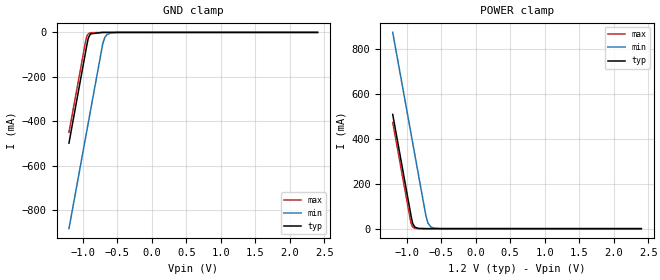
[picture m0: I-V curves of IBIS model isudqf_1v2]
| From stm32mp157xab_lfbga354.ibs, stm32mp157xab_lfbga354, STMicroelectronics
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[Model]   isudqf_1v2
Model_type Input
Polarity   Non-Inverting
Enable   Active-Low
| CAP_THRESHOLD on pad IOFT is "UDTCAPC" :
| Rising=20.00f vddiom   Falling=80.00f vddiom
| C_comp min and max val. don't necessarily correlate with the min and max pvt
| but are the smallest and greatest pad capacitance found.
| var   typ   min   max
C_comp   1.06084pF  1.04257pF  1.07176pF
|C_comp_pullup   463.02500fF  442.93500fF  461.80500fF
|C_comp_pulldown   597.81000fF  599.63000fF  609.95500fF
Vinl = 360.0mV
Vinh = 792.0mV
[Model Spec]
| TIME_THRESHOLD on pin ZIV11 is "CMOS" :
| Rising=40.00f vdd   Falling=60.00f vdd
Vinl 595.60000mV 448.60000mV 652.60000mV
Vinh 595.40000mV 448.40000mV 652.40000mV
| variable   typ   min   max
[Temperature Range] 25.0 140.0 -40.0
| variable   typ   min   max
[Voltage Range] 1.2V 900.0mV 1.32V
| variable   typ   min   max
[POWER Clamp Reference] 1.2V 900.0mV 1.32V
| variable   typ   min   max
[GND Clamp Reference] 0V 0V 0V
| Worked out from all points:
|   GND clamp passes 1 mA (typ) near -0.82 V on its own axis
|   POWER clamp passes 1 mA (typ) near -0.83 V on its own axis
[POWER Clamp]
-1.2V     508.8mA    874.1mA    473.5mA
-940mV    66.83mA    432.1mA    31.5mA
-930mV    49.83mA    415.1mA    19.15mA
-910mV    22.88mA    381.1mA    7.077mA
-880mV    7.117mA    330.1mA    1.59mA
-830mV    1.017mA    245.1mA    132uA
-720mV    14.05uA    58.12mA    553.9nA
-690mV    4.372uA    25.02mA    124.6nA
-650mV    921.8nA    8.137mA    17.13nA
-600mV    131.8nA    1.998mA    1.472nA
-490mV    1.914nA    90.93uA    27.04pA
2.4V      0A         0A         0A
[GND Clamp]
-1.2V     -497.4mA   -881.9mA   -449.4mA
-960mV    -89.41mA   -473.9mA   -41.39mA
-940mV    -55.41mA   -439.9mA   -16.04mA
-920mV    -26.33mA   -405.9mA   -6.567mA
-900mV    -12.55mA   -371.9mA   -2.962mA
-880mV    -6.152mA   -337.9mA   -1.53mA
-710mV    -61.3uA    -49.97mA   -15.96uA
-680mV    -25.68uA   -21.93mA   -9.154uA
-650mV    -12.16uA   -9.779mA   -6.928uA
-590mV    -5.24uA    -2.109mA   -4.904uA
-470mV    -2.231uA   -127.2uA   -1.904uA
2.4V      73.34pA    30.52nA    19.17pA
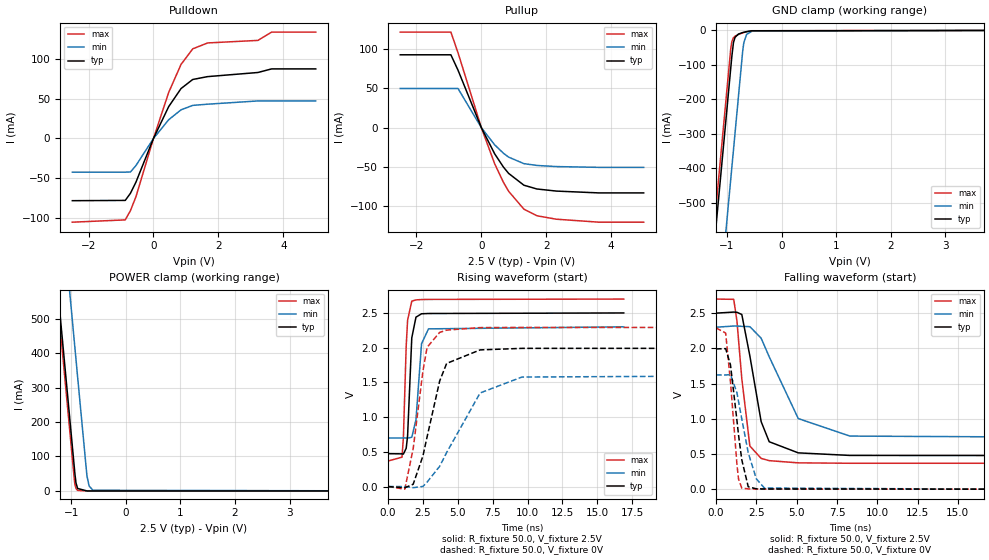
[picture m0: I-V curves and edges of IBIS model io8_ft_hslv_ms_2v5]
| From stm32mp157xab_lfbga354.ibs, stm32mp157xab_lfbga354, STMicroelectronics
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[Model]   io8_ft_hslv_ms_2v5
Model_type I/O
Polarity   Non-Inverting
Enable   Active-Low
| CAP_THRESHOLD on pad IOFT is "UDTCAPC" :
| Rising=20.00f vddiom   Falling=80.00f vddiom
| C_comp min and max val. don't necessarily correlate with the min and max pvt
| but are the smallest and greatest pad capacitance found.
| var   typ   min   max
C_comp   3.57714pF  3.54080pF  3.63508pF
|C_comp_pullup   2.11645pF  2.17895pF  2.03330pF
|C_comp_pulldown   1.46069pF  1.36185pF  1.60178pF
Vinl = 920.0mV
Vinh = 1.62V
Vmeas = 1.25V   | Reference voltage for timing measurements
Cref  = 50.0pF   | Timing specification test load capacitance value
Rref  = 100.0MOhm   | Timing specification test load resistance value
Vref  = 0V   | Timing specification test load voltage
[Model Spec]
| TIME_THRESHOLD on pin ZIV11 is "CMOS" :
| Rising=40.00f vdd   Falling=60.00f vdd
Vinl 1.03860V 964.60000mV 1.11860V
Vinh 1.36340V 1.26240V 1.44140V
| variable   typ   min   max
[Temperature Range] 25.0 140.0 -40.0
| variable   typ   min   max
[Voltage Range] 2.5V 2.3V 2.7V
| variable   typ   min   max
[POWER Clamp Reference] 2.5V 2.3V 2.7V
| variable   typ   min   max
[GND Clamp Reference] 0V 0V 0V
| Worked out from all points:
|   slope of the pulldown table from 0 to 0.375 V, typ, clamps not added: 11.3 ohm
|   slope of the pullup table from 0 to 0.375 V, typ, clamps not added: 12.3 ohm
|   GND clamp passes 1 mA (typ) near -0.52 V on its own axis
|   POWER clamp passes 1 mA (typ) near -0.83 V on its own axis
|   rising waveform, R_fixture 50.0, V_fixture 2.5V: 20-80 % time 255ps typ, 336ps min, 239ps max; typ from 0.473 V to 2.5 V
|   falling waveform, R_fixture 50.0, V_fixture 2.5V: 20-80 % time 928ps typ, 1.92ns min, 578ps max; typ from 2.5 V to 0.473 V
|   rising waveform, R_fixture 50.0, V_fixture 0V: 20-80 % time 1.36ns typ, 2.59ns min, 884ps max; typ from 0 V to 1.99 V
|   falling waveform, R_fixture 50.0, V_fixture 0V: 20-80 % time 629ps typ, 869ps min, 474ps max; typ from 1.99 V to 0 V
[POWER Clamp]
-2.5V     2.719A     3.084A     2.683A
-1.28V    644.8mA    1.01A      609.5mA
-1.26V    610.8mA    976.1mA    575.5mA
-1.04V    236.8mA    602.1mA    201.5mA
-940mV    66.83mA    432.1mA    31.5mA
-930mV    49.83mA    415.1mA    19.15mA
-910mV    22.88mA    381.1mA    7.077mA
-880mV    7.117mA    330.1mA    1.59mA
-710mV    9.523uA    43.89mA    337nA
-670mV    2.008uA    14.27mA    46.3nA
-600mV    132.9nA    1.998mA    1.599nA
5V        0A         0A         0A
[GND Clamp]
-2.5V     -2.779A    -3.101A    -2.723A
-1.26V    -670.8mA   -992.7mA   -614.5mA
-930mV    -109.8mA   -431.7mA   -53.54mA
-910mV    -75.83mA   -397.7mA   -32.67mA
-880mV    -35.28mA   -346.7mA   -21.39mA
-850mV    -20.07mA   -295.7mA   -16.99mA
-790mV    -10.9mA    -193.7mA   -12.02mA
-710mV    -6.374mA   -57.93mA   -7.219mA
-690mV    -5.545mA   -35.45mA   -6.225mA
-640mV    -3.775mA   -11.96mA   -4.068mA
-540mV    -1.354mA   -2.661mA   -1.223mA
5V        6.965nA    2.133uA    347.4pA
| variable   typ   min   max
[Pullup Reference] 2.5V 2.3V 2.7V
| variable   typ   min   max
[Pulldown Reference] 0V 0V 0V
[Pullup]
-2.5V     92.89mA    49.95mA    121.8mA
-940mV    92.89mA    49.95mA    121.8mA
-720mV    73.31mA    49.95mA    95.5mA
0V        9.19pA     1.4nA      5.79pA
410mV     -33.26mA   -21.8mA    -45.97mA
680mV     -50.15mA   -32.52mA   -69.57mA
840mV     -58.17mA   -37.44mA   -80.95mA
1.31V     -73.2mA    -45.74mA   -103.7mA
1.71V     -78mA      -48.02mA   -112.1mA
2.31V     -80.68mA   -49.47mA   -116.5mA
3.63V     -83.02mA   -50.48mA   -120.3mA
5V        -83.02mA   -50.48mA   -120.3mA
[Pulldown]
-2.5V     -78.63mA   -42.6mA    -105.8mA
-870mV    -78.28mA   -42.6mA    -102.9mA
-710mV    -69.32mA   -42.37mA   -91.24mA
-540mV    -55.23mA   -34.22mA   -73.64mA
0V        0A         -2pA       0A
470mV     40.29mA    23.69mA    58.27mA
850mV     63.07mA    36.18mA    93.59mA
1.21V     74.52mA    41.78mA    113.2mA
1.67V     78.14mA    43.3mA     120.7mA
3.22V     83.36mA    47.41mA    123.9mA
3.64V     87.89mA    47.41mA    134.4mA
5V        87.89mA    47.41mA    134.4mA
[Ramp]
dV/dt_r 1.19545V/1.35568ns 973.40258mV/2.59049ns 1.37489V/880.07309ps
dV/dt_f 1.21605V/925.50477ps 960.47155mV/1.91927ns 1.39953V/573.33804ps
R_load = 50.0
| Removed startup time: 0s 0s 0s  .
| Removed end time: 16.9ns.
[Rising Waveform]
R_fixture   = 50.0
V_fixture   = 2.5V
V_fixture_min = 2.3V
V_fixture_max = 2.7V
0s        473.2mV    699.2mV    367.5mV
1ns       470.7mV    699.4mV    423.3mV
1.1ns     467.8mV    699.3mV    711.2mV
1.3ns     551.2mV    699.1mV    2.024V
1.4ns     728.5mV    698.3mV    2.395V
1.7ns     2.141V     709.2mV    2.67V
2ns       2.439V     960.9mV    2.688V
2.4ns     2.488V     2.057V     2.693V
2.9ns     2.492V     2.271V     2.695V
16.9ns    2.5V       2.3V       2.7V
| Removed startup time: 0s 0s 0s  .
| Removed end time: 54.9ns.
[Falling Waveform]
R_fixture   = 50.0
V_fixture   = 2.5V
V_fixture_min = 2.3V
V_fixture_max = 2.7V
0s        2.5V       2.3V       2.7V
1.1ns     2.515V     2.317V     2.696V
1.3ns     2.512V     2.317V     2.388V
1.6ns     2.481V     2.312V     1.571V
2.1ns     1.893V     2.308V     612.5mV
2.8ns     959.1mV    2.144V     437mV
3.3ns     673.5mV    1.88V      405mV
5.1ns     515.7mV    1.003V     373.7mV
8.3ns     479.1mV    753.9mV    367.9mV
54.9ns    473.2mV    699.2mV    367.5mV
| Removed startup time: 0s 0s 0s  .
| Removed end time: 54.9ns.
[Rising Waveform]
R_fixture   = 50.0
V_fixture   = 0V
V_fixture_min = 0V
V_fixture_max = 0V
0s        55.42nV    78.87nV    -3.786uV
1.2ns     -17.78mV   49.94uV    -37.72mV
1.8ns     33.06mV    -16.52mV   544.3mV
2.5ns     440.9mV    1.382mV    1.664V
2.8ns     716.9mV    64.67mV    2.006V
3.7ns     1.52V      291.4mV    2.22V
4.2ns     1.773V     489.6mV    2.253V
6.6ns     1.968V     1.348V     2.289V
9.6ns     1.99V      1.577V     2.291V
54.9ns    1.992V     1.622V     2.291V
| Removed startup time: 0s 0s 0s  .
| Removed end time: 16.9ns.
[Falling Waveform]
R_fixture   = 50.0
V_fixture   = 0V
V_fixture_min = 0V
V_fixture_max = 0V
0s        1.992V     1.622V     2.291V
600ps     1.996V     1.622V     2.217V
900ps     1.764V     1.626V     1.52V
1.3ns     974.4mV    1.369V     348.3mV
1.4ns     765.3mV    1.241V     141.8mV
1.6ns     416.5mV    996.7mV    14.99mV
2ns       33.71mV    515.9mV    4.27mV
2.5ns     5.236mV    147.1mV    2.52mV
3ns       3.046mV    16.4mV     1.808mV
16.9ns    6.795uV    40.09uV    3.014uV
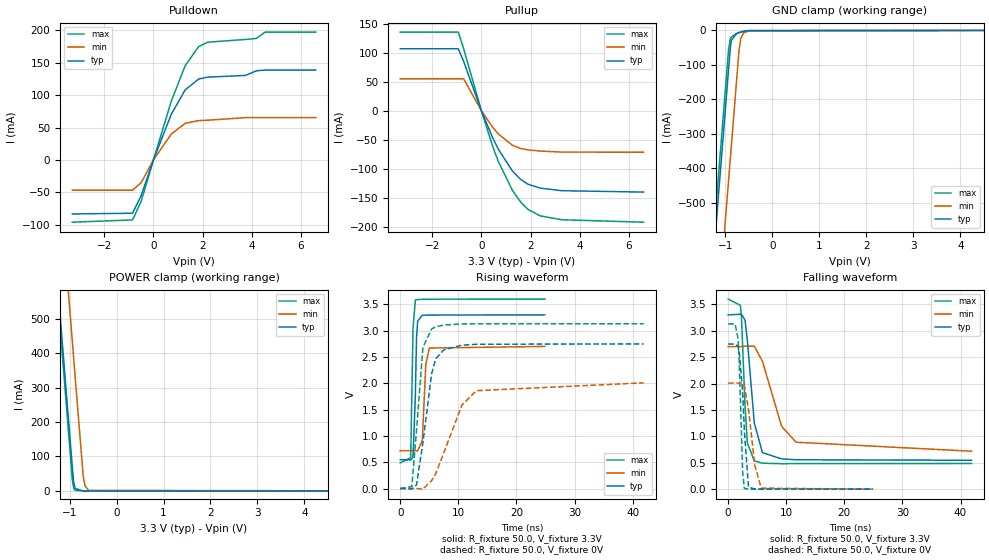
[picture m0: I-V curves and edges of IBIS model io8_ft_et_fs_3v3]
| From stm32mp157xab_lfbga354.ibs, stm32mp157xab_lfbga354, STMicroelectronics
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[Model]   io8_ft_et_fs_3v3
Model_type I/O
Polarity   Non-Inverting
Enable   Active-Low
| CAP_THRESHOLD on pad IOFT is "UDTCAPC" :
| Rising=20.00f vddiom   Falling=80.00f vddiom
| C_comp min and max val. don't necessarily correlate with the min and max pvt
| but are the smallest and greatest pad capacitance found.
| var   typ   min   max
C_comp   3.68632pF  3.64973pF  3.70805pF
|C_comp_pullup   2.21620pF  2.27950pF  2.11835pF
|C_comp_pulldown   1.47012pF  1.37023pF  1.58970pF
Vinl = 1.08V
Vinh = 2.16V
Vmeas = 1.65V   | Reference voltage for timing measurements
Cref  = 50.0pF   | Timing specification test load capacitance value
Rref  = 100.0MOhm   | Timing specification test load resistance value
Vref  = 0V   | Timing specification test load voltage
[Model Spec]
| TIME_THRESHOLD on pin ZIV11 is "CMOS" :
| Rising=40.00f vdd   Falling=60.00f vdd
Vinl 1.36060V 1.12960V 1.47360V
Vinh 1.71540V 1.45040V 1.82940V
| variable   typ   min   max
[Temperature Range] 25.0 140.0 -40.0
| variable   typ   min   max
[Voltage Range] 3.3V 2.7V 3.6V
| variable   typ   min   max
[POWER Clamp Reference] 3.3V 2.7V 3.6V
| variable   typ   min   max
[GND Clamp Reference] 0V 0V 0V
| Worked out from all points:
|   slope of the pulldown table from 0 to 0.495 V, typ, clamps not added: 9.86 ohm
|   slope of the pullup table from 0 to 0.495 V, typ, clamps not added: 9.93 ohm
|   GND clamp passes 1 mA (typ) near -0.52 V on its own axis
|   POWER clamp passes 1 mA (typ) near -0.83 V on its own axis
|   rising waveform, R_fixture 50.0, V_fixture 3.3V: 20-80 % time 297ps typ, 428ps min, 262ps max; typ from 0.547 V to 3.3 V
|   falling waveform, R_fixture 50.0, V_fixture 3.3V: 20-80 % time 1.31ns typ, 3.25ns min, 738ps max; typ from 3.3 V to 0.547 V
|   rising waveform, R_fixture 50.0, V_fixture 0V: 20-80 % time 1.9ns typ, 4.15ns min, 1.24ns max; typ from 0 V to 2.75 V
|   falling waveform, R_fixture 50.0, V_fixture 0V: 20-80 % time 775ps typ, 1.26ns min, 523ps max; typ from 2.75 V to 0 V
[POWER Clamp]
-3.3V     4.079A     4.444A     4.043A
-1.46V    950.8mA    1.316A     915.5mA
-1.28V    644.8mA    1.01A      609.5mA
-1.09V    321.8mA    687.1mA    286.5mA
-1.07V    287.8mA    653.1mA    252.5mA
-940mV    66.83mA    432.1mA    31.5mA
-910mV    22.88mA    381.1mA    7.077mA
-880mV    7.117mA    330.1mA    1.59mA
-710mV    9.525uA    43.89mA    337.5nA
-670mV    2.01uA     14.27mA    46.78nA
-590mV    92.5nA     1.508mA    1.51nA
6.6V      0A         0A         0A
[GND Clamp]
-3.3V     -4.139A    -4.461A    -4.081A
-1.26V    -670.8mA   -992.8mA   -613.3mA
-1.1V     -398.8mA   -720.8mA   -341.3mA
-930mV    -109.8mA   -431.8mA   -52.32mA
-890mV    -44.91mA   -363.8mA   -23.04mA
-870mV    -28.43mA   -329.8mA   -18.86mA
-760mV    -8.879mA   -142.8mA   -9.749mA
-710mV    -6.383mA   -58.04mA   -7.036mA
-670mV    -4.798mA   -22.41mA   -5.193mA
-610mV    -2.902mA   -7.057mA   -2.962mA
-500mV    -778.4uA   -1.643mA   -611.3uA
6.6V      9.268nA    3.087uA    468pA
| variable   typ   min   max
[Pullup Reference] 3.3V 2.7V 3.6V
| variable   typ   min   max
[Pulldown Reference] 0V 0V 0V
[Pullup]
-3.3V     106.6mA    54.84mA    135.3mA
-940mV    106.6mA    54.84mA    135.3mA
-720mV    84.69mA    54.84mA    106.6mA
0V        11.24pA    1.438nA    7.78pA
470mV     -47.64mA   -29.17mA   -62.71mA
690mV     -66.39mA   -40.06mA   -87.4mA
1.26V     -103.7mA   -59.49mA   -136.9mA
1.59V     -118mA     -65.02mA   -156.8mA
1.89V     -126.5mA   -67.46mA   -169.8mA
2.39V     -133.2mA   -69.44mA   -181mA
3.27V     -137.7mA   -71.26mA   -187.7mA
6.6V      -140.1mA   -71.49mA   -191.9mA
[Pulldown]
-3.3V     -83.56mA   -46.9mA    -96.31mA
-850mV    -82.46mA   -46.9mA    -92.78mA
-500mV    -55.19mA   -35.23mA   -63.97mA
0V        30fA       -2pA       200fA
720mV     70.07mA    39.69mA    90.11mA
1.29V     108.2mA    56.55mA    145.7mA
1.84V     125mA      60.7mA     175.1mA
2.21V     127.9mA    61.3mA     181.9mA
3.74V     130.5mA    65.29mA    186.1mA
4.18V     137.6mA    65.29mA    187.7mA
4.54V     138.8mA    65.29mA    197.5mA
6.6V      138.8mA    65.29mA    197.5mA
[Ramp]
dV/dt_r 1.64855V/1.89725ns 1.20468V/4.14499ns 1.87853V/1.24008ns
dV/dt_f 1.65162V/1.31006ns 1.18883V/3.24747ns 1.86819V/736.45008ps
R_load = 50.0
| Removed startup time: 0s 0s 0s  .
| Removed end time: 24.9ns.
[Rising Waveform]
R_fixture   = 50.0
V_fixture   = 3.3V
V_fixture_min = 2.7V
V_fixture_max = 3.6V
0s        547.3mV    718.4mV    486.3mV
1.8ns     543.9mV    718.4mV    585.2mV
2.2ns     590.8mV    718.4mV    3.037V
2.6ns     1.76V      718.5mV    3.581V
2.8ns     2.857V     717.9mV    3.59V
3ns       3.181V     716.3mV    3.591V
3.8ns     3.293V     910.7mV    3.595V
4.4ns     3.294V     2.355V     3.596V
5ns       3.296V     2.669V     3.597V
24.9ns    3.3V       2.7V       3.6V
| Removed startup time: 0s 0s 0s  .
| Removed end time: 41.9ns.
[Falling Waveform]
R_fixture   = 50.0
V_fixture   = 3.3V
V_fixture_min = 2.7V
V_fixture_max = 3.6V
0s        3.3V       2.7V       3.6V
2.1ns     3.313V     2.7V       3.481V
2.3ns     3.311V     2.699V     3.246V
2.9ns     3.203V     2.709V     1.588V
3.3ns     2.824V     2.709V     872.7mV
4.5ns     1.255V     2.706V     536.5mV
5.9ns     692mV      2.423V     491.8mV
9.2ns     574mV      1.188V     482.3mV
11.7ns    556.5mV    889.2mV    484.5mV
41.9ns    547.3mV    718.6mV    486.3mV
| Removed startup time: 0s 0s 0s  .
| Removed end time: 41.9ns.
[Rising Waveform]
R_fixture   = 50.0
V_fixture   = 0V
V_fixture_min = 0V
V_fixture_max = 0V
0s        605.8nV    443.2nV    -450.2nV
2ns       -10.22mV   1.521uV    37.31mV
2.8ns     69.22mV    237.4uV    1.1V
3.9ns     868.5mV    -12.54mV   2.682V
5.4ns     2.178V     149.9mV    3.032V
6.1ns     2.466V     279.3mV    3.072V
7.5ns     2.635V     680.1mV    3.107V
10.6ns    2.724V     1.582V     3.127V
13.1ns    2.741V     1.859V     3.13V
41.9ns    2.748V     2.008V     3.131V
| Removed startup time: 0s 0s 0s  .
| Removed end time: 24.9ns.
[Falling Waveform]
R_fixture   = 50.0
V_fixture   = 0V
V_fixture_min = 0V
V_fixture_max = 0V
0s        2.748V     2.008V     3.131V
1.2ns     2.747V     2.008V     3.127V
1.7ns     2.706V     2.008V     2.851V
1.9ns     2.615V     2.008V     2.43V
2.5ns     1.824V     2.012V     311.5mV
2.8ns     1.089V     1.951V     11.64mV
3.5ns     39.57mV    1.516V     3.002mV
4.6ns     3.004mV    441.3mV    1.696mV
5.7ns     1.827mV    19.43mV    1.15mV
24.9ns    5.096uV    74.95uV    697.7nV
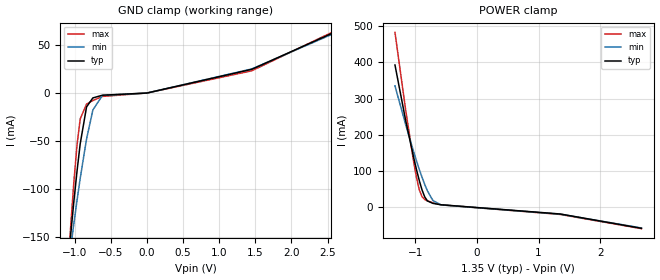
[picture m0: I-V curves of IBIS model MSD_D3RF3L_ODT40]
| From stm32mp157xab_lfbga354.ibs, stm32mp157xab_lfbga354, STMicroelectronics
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[Model] MSD_D3RF3L_ODT40
Model_type   Input
C_comp 2.184pF   2.148pF   2.230pF
Vinh = 810.000mV
Vinl = 540.000mV
[Temperature Range]   25.000   125.000   -40.000
[Voltage Range]   1.350V   1.283V   1.450V
[GND Clamp Reference]   0.00V   0.00V   0.00V
[POWER Clamp Reference]   1.350V   1.283V   1.450V
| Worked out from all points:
|   GND clamp passes 1 mA (typ) near -0.50 V on its own axis
|   POWER clamp passes 1 mA (typ) near -0.16 V on its own axis
[GND Clamp]
-1.318V   -386mA     -324.8mA   -479.6mA
-1.098V   -185.2mA   -188.1mA   -190.1mA
-1.055V   -148.4mA   -162mA     -139.7mA
-1.011V   -113.7mA   -136.7mA   -93.64mA
-966.7mV  -81.62mA   -112.3mA   -54.4mA
-922.7mV  -53.04mA   -89.13mA   -27.03mA
-834.9mV  -14.5mA    -47.92mA   -11.5mA
-747mV    -5.076mA   -17.64mA   -7.832mA
-615.1mV  -2.272mA   -2.496mA   -3.524mA
200nV     3.259nA    3.159nA    3.265nA
1.45V     24.75mA    25.13mA    23.19mA
2.68V     66.36mA    65.17mA    67.71mA
[Power Clamp]
-1.33V    393.1mA    335.1mA    483.3mA
-1.155V   238mA      227mA      266.3mA
-1.023V   133.6mA    150.2mA    120.9mA
-978.8mV  101.9mA    126.3mA    79.54mA
-934.9mV  72.52mA    103.4mA    47.08mA
-890.9mV  46.92mA    81.96mA    28.32mA
-847mV    27.56mA    62.03mA    20.39mA
-803mV    16.66mA    44.11mA    16.6mA
-715.1mV  9.837mA    17.83mA    11.34mA
-583.3mV  5.975mA    5.57mA     5.775mA
1.35V     -19.6mA    -20.02mA   -20.84mA
2.668V    -59.26mA   -58.29mA   -60.21mA
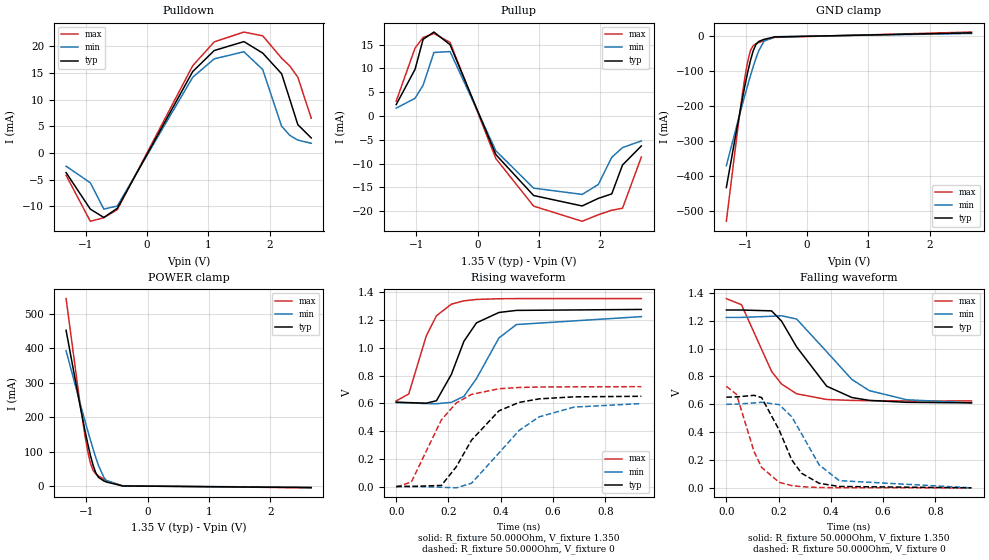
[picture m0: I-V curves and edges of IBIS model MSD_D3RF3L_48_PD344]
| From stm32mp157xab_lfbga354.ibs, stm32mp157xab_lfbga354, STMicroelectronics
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[Model] MSD_D3RF3L_48_PD344
Model_type   I/O
C_comp 2.333pF   2.249pF   2.455pF
Vinh = 810.000mV
Vinl = 540.000mV
Vmeas = 675.000mV
Vref = 675.000mV
[Model Spec]
Vinh   810.000mV   777.000mV   860.000mV
Vinl   540.000mV   507.000mV   590.000mV
Vmeas   675.000mV   642.000mV   725.000mV
Vref   675.000mV   642.000mV   725.000mV
[Temperature Range]   25.000   125.000   -40.000
[Voltage Range]   1.350V   1.283V   1.450V
[GND Clamp Reference]   0.00V   0.00V   0.00V
[Pulldown Reference]   0.00V   0.00V   0.00V
[POWER Clamp Reference]   1.350V   1.283V   1.450V
[Pullup Reference]   1.350V   1.283V   1.450V
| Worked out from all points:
|   slope of the pulldown table from 0 to 0.203 V, typ, clamps not added: 42.2 ohm
|   slope of the pullup table from 0 to 0.203 V, typ, clamps not added: 34.5 ohm
|   GND clamp passes 1 mA (typ) near -0.41 V on its own axis
|   POWER clamp passes 1 mA (typ) near -0.41 V on its own axis
|   rising waveform, R_fixture 50.000Ohm, V_fixture 1.350: 20-80 % time 92.1ps typ, 116ps min, 78.7ps max; typ from 0.608 V to 1.28 V
|   rising waveform, R_fixture 50.000Ohm, V_fixture 0: 20-80 % time 148ps typ, 181ps min, 126ps max; typ from 0.001 V to 0.651 V
|   falling waveform, R_fixture 50.000Ohm, V_fixture 1.350: 20-80 % time 146ps typ, 180ps min, 113ps max; typ from 1.28 V to 0.61 V
|   falling waveform, R_fixture 50.000Ohm, V_fixture 0: 20-80 % time 95.8ps typ, 116ps min, 79.2ps max; typ from 0.651 V to 0 V
[GND Clamp]
-1.318V   -432.8mA   -370.3mA   -528.8mA
-1.142V   -260.6mA   -252.7mA   -280.2mA
-1.055V   -178.2mA   -195.3mA   -165.2mA
-1.011V   -139.1mA   -167.2mA   -114.1mA
-966.7mV  -102.3mA   -139.7mA   -71.26mA
-922.7mV  -69.52mA   -113.2mA   -41.65mA
-878.8mV  -42.92mA   -87.94mA   -28.29mA
-834.9mV  -25.34mA   -64.54mA   -23.37mA
-790.9mV  -16.86mA   -43.9mA    -20.2mA
-703mV    -10.78mA   -15.99mA   -14.6mA
-527.3mV  -3.885mA   -3.295mA   -5.182mA
2.68V     7.735mA    6.026mA    10.03mA
[Power Clamp]
-1.33V    451.9mA    392.5mA    543.7mA
-1.111V   241.7mA    247mA      250.6mA
-1.023V   162.1mA    190.1mA    147.8mA
-978.8mV  125mA      162.2mA    103.3mA
-934.9mV  90.96mA    135mA      67.89mA
-890.9mV  61.61mA    108.7mA    46.32mA
-847mV    39.32mA    83.78mA    35.87mA
-803mV    26.01mA    60.99mA    29.83mA
-715.1mV  15.42mA    26.29mA    20.43mA
-671.2mV  12.23mA    16.24mA    16.32mA
-407.6mV  863.9uA    1.131mA    1.056mA
2.668V    -3.889mA   -3.241mA   -4.623mA
[Pulldown]
-1.318V   -3.7mA     -2.5mA     -4.2mA
-922.7mV  -10.55mA   -5.6mA     -12.83mA
-703mV    -12.11mA   -10.54mA   -12.17mA
-483.3mV  -10.41mA   -9.972mA   -10.65mA
747mV     15.26mA    14.19mA    16.35mA
1.098V    19.2mA     17.64mA    20.82mA
1.582V    20.88mA    18.97mA    22.67mA
1.889V    18.72mA    15.63mA    21.96mA
2.197V    14.84mA    5mA        17.77mA
2.329V    10.1mA     3.3mA      16.32mA
2.461V    5.3mA      2.4mA      14.2mA
2.68V     2.8mA      1.8mA      6.5mA
[Pullup]
-1.33V    2.4mA      1.652mA    3.135mA
-1.023V   9.8mA      3.715mA    14.27mA
-890.9mV  16.12mA    6.482mA    16.51mA
-715.1mV  17.65mA    13.36mA    17.35mA
-451.5mV  14.99mA    13.54mA    15.47mA
295.4mV   -8.125mA   -7.33mA    -8.964mA
910.6mV   -16.72mA   -15.17mA   -18.95mA
1.702V    -18.92mA   -16.49mA   -22.14mA
1.965V    -17.33mA   -14.42mA   -20.77mA
2.185V    -16.38mA   -8.694mA   -19.82mA
2.361V    -10.3mA    -6.643mA   -19.39mA
2.668V    -6.3mA     -5.248mA   -8.621mA
[Ramp]
R_load=50.000Ohm
dV/dt_r   395.820mV/121.000ps  365.579mV/149.500ps  435.510mV/103.000ps
dV/dt_f   395.820mV/122.000ps  365.609mV/149.500ps  435.510mV/96.500ps
[Rising waveform]
R_fixture=50.000Ohm
V_fixture=1.350
V_fixture_min=1.283
V_fixture_max=1.450
0s        608.4mV    604.8mV    617.3mV
48ps      605.2mV    602.4mV    667.5mV
115ps     600.8mV    598.2mV    1.086V
154ps     618.7mV    597mV      1.231V
211ps     808.3mV    607mV      1.315V
259ps     1.047V     650.4mV    1.339V
307ps     1.18V      778mV      1.349V
393ps     1.255V     1.071V     1.354V
460ps     1.27V      1.168V     1.355V
938ps     1.277V     1.225V     1.355V
[Rising waveform]
R_fixture=50.000Ohm
V_fixture=0
0s        576.1uV    582.4uV    -3.917mV
58ps      315.7uV    804.5uV    32.69mV
173ps     7.95mV     -5.07mV    481.4mV
230ps     142.8mV    -9.445mV   602.7mV
288ps     334.1mV    23.45mV    664.3mV
393ps     545.7mV    241.6mV    705mV
470ps     606.5mV    403.8mV    714.3mV
547ps     632.1mV    502.4mV    717.5mV
681ps     646.7mV    572.8mV    719.1mV
938ps     650.6mV    598.1mV    719.9mV
[Falling waveform]
R_fixture=50.000Ohm
V_fixture=1.350
V_fixture_min=1.283
V_fixture_max=1.450
0s        1.277V     1.224V     1.359V
58ps      1.277V     1.224V     1.315V
173ps     1.271V     1.232V     836.8mV
211ps     1.198V     1.236V     745.9mV
269ps     1.012V     1.212V     675.5mV
384ps     730mV      977.5mV    634.5mV
480ps     648.8mV    778.9mV    627.8mV
547ps     628mV      698.2mV    626.1mV
690ps     614.1mV    632.4mV    624.3mV
938ps     610.2mV    610.5mV    623.9mV
[Falling waveform]
R_fixture=50.000Ohm
V_fixture=0
0s        650.9mV    599.8mV    729mV
39ps      653.2mV    601.1mV    671.2mV
106ps     664.2mV    609.7mV    260.7mV
135ps     648.3mV    614.5mV    146.6mV
202ps     415.8mV    597.5mV    39.68mV
250ps     201.4mV    511.3mV    16.25mV
288ps     104.6mV    387.9mV    8.148mV
355ps     32.76mV    165mV      2.424mV
432ps     9.672mV    51.68mV    621.6uV
938ps     17.06uV    123.1uV    5.024uV
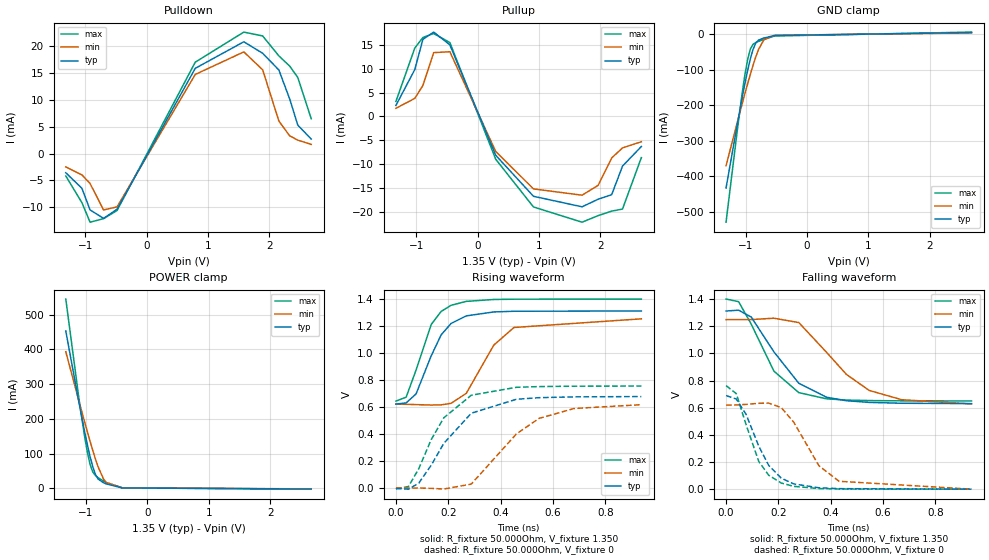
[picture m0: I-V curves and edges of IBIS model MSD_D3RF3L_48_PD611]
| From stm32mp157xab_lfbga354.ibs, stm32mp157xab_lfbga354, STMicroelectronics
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[Model] MSD_D3RF3L_48_PD611
Model_type   I/O
C_comp 2.439pF   2.355pF   2.563pF
Vinh = 810.000mV
Vinl = 540.000mV
Vmeas = 675.000mV
Vref = 675.000mV
[Model Spec]
Vinh   810.000mV   777.000mV   860.000mV
Vinl   540.000mV   507.000mV   590.000mV
Vmeas   675.000mV   642.000mV   725.000mV
Vref   675.000mV   642.000mV   725.000mV
[Temperature Range]   25.000   125.000   -40.000
[Voltage Range]   1.350V   1.283V   1.450V
[GND Clamp Reference]   0.00V   0.00V   0.00V
[Pulldown Reference]   0.00V   0.00V   0.00V
[POWER Clamp Reference]   1.350V   1.283V   1.450V
[Pullup Reference]   1.350V   1.283V   1.450V
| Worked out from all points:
|   slope of the pulldown table from 0 to 0.203 V, typ, clamps not added: 42.2 ohm
|   slope of the pullup table from 0 to 0.203 V, typ, clamps not added: 34.5 ohm
|   GND clamp passes 1 mA (typ) near -0.40 V on its own axis
|   POWER clamp passes 1 mA (typ) near -0.41 V on its own axis
|   rising waveform, R_fixture 50.000Ohm, V_fixture 1.350: 20-80 % time 95ps typ, 118ps min, 80.7ps max; typ from 0.62 V to 1.31 V
|   rising waveform, R_fixture 50.000Ohm, V_fixture 0: 20-80 % time 155ps typ, 186ps min, 133ps max; typ from -0.004 V to 0.676 V
|   falling waveform, R_fixture 50.000Ohm, V_fixture 1.350: 20-80 % time 155ps typ, 188ps min, 123ps max; typ from 1.31 V to 0.63 V
|   falling waveform, R_fixture 50.000Ohm, V_fixture 0: 20-80 % time 102ps typ, 120ps min, 84.4ps max; typ from 0.689 V to 0 V
[GND Clamp]
-1.318V   -433.8mA   -371.2mA   -530.1mA
-1.142V   -261.4mA   -253.4mA   -281.2mA
-1.055V   -178.9mA   -195.9mA   -166mA
-1.011V   -139.7mA   -167.8mA   -114.9mA
-966.7mV  -102.9mA   -140.2mA   -72.01mA
-922.7mV  -70.05mA   -113.7mA   -42.34mA
-878.8mV  -43.4mA    -88.34mA   -28.91mA
-834.9mV  -25.77mA   -64.88mA   -23.94mA
-790.9mV  -17.25mA   -44.21mA   -20.71mA
-703mV    -11.07mA   -16.23mA   -15mA
-527.3mV  -4.022mA   -3.409mA   -5.364mA
2.68V     4.353mA    3.39mA     5.636mA
[Power Clamp]
-1.33V    453mA      393.4mA    545.1mA
-1.111V   242.5mA    247.8mA    251.6mA
-1.023V   162.8mA    190.7mA    148.7mA
-978.8mV  125.6mA    162.8mA    104.1mA
-934.9mV  91.56mA    135.5mA    68.65mA
-890.9mV  62.16mA    109.2mA    47mA
-847mV    39.83mA    84.22mA    36.49mA
-803mV    26.46mA    61.4mA     30.39mA
-715.1mV  15.76mA    26.62mA    20.87mA
-671.2mV  12.53mA    16.52mA    16.7mA
-407.6mV  918uA      1.198mA    1.12mA
2.668V    -2.188mA   -1.824mA   -2.601mA
[Pulldown]
-1.318V   -3.6mA     -2.5mA     -4.2mA
-1.055V   -6.5mA     -4mA       -9.2mA
-922.7mV  -10.54mA   -5.6mA     -12.83mA
-703mV    -12.12mA   -10.54mA   -12.17mA
-483.3mV  -10.41mA   -9.971mA   -10.65mA
790.9mV   15.91mA    14.77mA    17.06mA
1.582V    20.87mA    18.98mA    22.68mA
1.889V    18.72mA    15.63mA    21.96mA
2.153V    15.6mA     6.07mA     18.23mA
2.329V    10.2mA     3.3mA      16.33mA
2.461V    5.3mA      2.5mA      14.2mA
2.68V     2.7mA      1.7mA      6.5mA
[Pullup]
-1.33V    2.3mA      1.705mA    3.135mA
-1.023V   9.8mA      3.767mA    14.3mA
-890.9mV  16.12mA    6.467mA    16.52mA
-715.1mV  17.65mA    13.35mA    17.35mA
-451.5mV  14.98mA    13.54mA    15.46mA
295.4mV   -8.125mA   -7.33mA    -8.964mA
910.6mV   -16.72mA   -15.17mA   -18.95mA
1.702V    -18.92mA   -16.49mA   -22.14mA
1.965V    -17.33mA   -14.42mA   -20.77mA
2.185V    -16.38mA   -8.694mA   -19.82mA
2.361V    -10.4mA    -6.595mA   -19.39mA
2.668V    -6.3mA     -5.3mA     -8.621mA
[Ramp]
R_load=50.000Ohm
dV/dt_r   406.740mV/125.500ps  373.829mV/154.500ps  450.240mV/107.500ps
dV/dt_f   406.740mV/128.500ps  373.829mV/156.500ps  450.240mV/103.500ps
[Rising waveform]
R_fixture=50.000Ohm
V_fixture=1.350
V_fixture_min=1.283
V_fixture_max=1.450
0s        620.4mV    621.1mV    642.5mV
39ps      629mV      619mV      671.3mV
77ps      695.7mV    616.5mV    871.7mV
135ps     977.4mV    613.4mV    1.209V
173ps     1.132V     614.9mV    1.305V
211ps     1.216V     626.3mV    1.35V
269ps     1.272V     700mV      1.379V
374ps     1.301V     1.056V     1.393V
451ps     1.306V     1.186V     1.395V
938ps     1.308V     1.25V      1.396V
[Rising waveform]
R_fixture=50.000Ohm
V_fixture=0
0s        -4.089mV   622.1uV    -4.131mV
48ps      -7.836mV   816.8uV    11.78mV
87ps      35.9mV     433.1uV    142.3mV
135ps     169.6mV    -1.862mV   358.3mV
183ps     330.3mV    -6.845mV   519.2mV
288ps     553mV      29.55mV    685.9mV
460ps     655.8mV    399.3mV    744.3mV
547ps     667.8mV    514.9mV    749.7mV
681ps     673.8mV    587.8mV    752.5mV
938ps     676mV      616.1mV    754mV
[Falling waveform]
R_fixture=50.000Ohm
V_fixture=1.350
V_fixture_min=1.283
V_fixture_max=1.450
0s        1.312V     1.249V     1.4V
48ps      1.318V     1.249V     1.381V
96ps      1.268V     1.249V     1.216V
183ps     1.011V     1.259V     869.2mV
278ps     780mV      1.227V     710.9mV
384ps     677mV      1.008V     665.2mV
460ps     651.3mV    845.2mV    656.2mV
547ps     639mV      727.2mV    652.5mV
671ps     632.7mV    658.8mV    650.4mV
938ps     630.1mV    627.9mV    649.4mV
[Falling waveform]
R_fixture=50.000Ohm
V_fixture=0
0s        689.2mV    618.9mV    762.7mV
39ps      664.1mV    620.4mV    703.9mV
77ps      549.6mV    624.5mV    472.5mV
125ps     316.3mV    632.3mV    204.2mV
163ps     175.3mV    633.8mV    102.7mV
211ps     80.9mV     600.5mV    45.12mV
259ps     38.53mV    492.6mV    20.68mV
355ps     10.22mV    172.3mV    4.557mV
432ps     3.739mV    57.96mV    1.388mV
938ps     25.78uV    228.7uV    -7.197uV
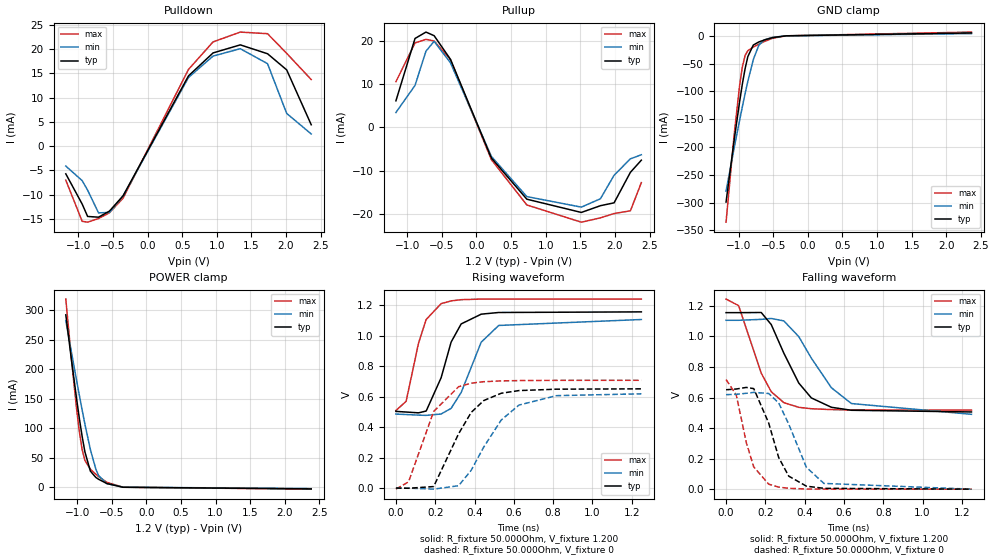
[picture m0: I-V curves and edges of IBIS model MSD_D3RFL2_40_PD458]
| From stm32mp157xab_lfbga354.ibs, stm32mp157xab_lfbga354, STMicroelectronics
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[Model] MSD_D3RFL2_40_PD458
Model_type   I/O
C_comp 2.402pF   2.316pF   2.526pF
Vinh = 820.000mV
Vinl = 380.000mV
Vmeas = 600.000mV
Vref = 600.000mV
[Model Spec]
Vinh   820.000mV   790.000mV   870.000mV
Vinl   380.000mV   350.000mV   430.000mV
Vmeas   600.000mV   570.000mV   650.000mV
Vref   600.000mV   570.000mV   650.000mV
[Temperature Range]   25.000   125.000   -40.000
[Voltage Range]   1.200V   1.140V   1.300V
[GND Clamp Reference]   0.00V   0.00V   0.00V
[Pulldown Reference]   0.00V   0.00V   0.00V
[POWER Clamp Reference]   1.200V   1.140V   1.300V
[Pullup Reference]   1.200V   1.140V   1.300V
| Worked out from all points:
|   slope of the pulldown table from 0 to 0.18 V, typ, clamps not added: 35.6 ohm
|   slope of the pullup table from 0 to 0.18 V, typ, clamps not added: 29.6 ohm
|   GND clamp passes 1 mA (typ) near -0.40 V on its own axis
|   POWER clamp passes 1 mA (typ) near -0.41 V on its own axis
|   rising waveform, R_fixture 50.000Ohm, V_fixture 1.200: 20-80 % time 94ps typ, 121ps min, 80.6ps max; typ from 0.504 V to 1.16 V
|   rising waveform, R_fixture 50.000Ohm, V_fixture 0: 20-80 % time 153ps typ, 187ps min, 130ps max; typ from 0.001 V to 0.652 V
|   falling waveform, R_fixture 50.000Ohm, V_fixture 1.200: 20-80 % time 156ps typ, 197ps min, 122ps max; typ from 1.16 V to 0.506 V
|   falling waveform, R_fixture 50.000Ohm, V_fixture 0: 20-80 % time 97.5ps typ, 122ps min, 81.8ps max; typ from 0.651 V to 0 V
[GND Clamp]
-1.182V   -299.1mA   -279.3mA   -335.3mA
-1.064V   -187mA     -201.5mA   -177mA
-984.9mV  -117.6mA   -151.3mA   -88.16mA
-945.5mV  -86.22mA   -127.1mA   -55.37mA
-906.1mV  -58.84mA   -103.8mA   -35.26mA
-866.7mV  -37.35mA   -81.5mA    -26.87mA
-787.9mV  -16.73mA   -42.8mA    -20.29mA
-709.1mV  -11.25mA   -17.38mA   -15.2mA
-630.3mV  -7.745mA   -7.438mA   -10.54mA
-512.1mV  -3.498mA   -2.984mA   -4.633mA
-315.1mV  -158.7uA   -224.9uA   -147.6uA
2.364V    4.99mA     3.837mA    6.535mA
[Power Clamp]
-1.164V   292mA      282.1mA    318.7mA
-1.085V   218.3mA    230.5mA    219.6mA
-1.006V   148.1mA    179.7mA    130.7mA
-966.7mV  115.5mA    154.8mA    92.95mA
-927.3mV  85.81mA    130.6mA    63.61mA
-887.9mV  60.1mA     107.1mA    45.52mA
-809.1mV  27.58mA    64.08mA    30.85mA
-730.3mV  16.84mA    30.96mA    22.19mA
-690.9mV  13.77mA    20.14mA    18.34mA
-572.7mV  6.533mA    6.447mA    8.649mA
-336.4mV  178.2uA    339.3uA    207.6uA
2.382V    -2.569mA   -2.119mA   -3.047mA
[Pulldown]
-1.182V   -5.7mA     -4.1mA     -7mA
-945.5mV  -11.92mA   -7.1mA     -15.47mA
-866.7mV  -14.47mA   -9.06mA    -15.65mA
-709.1mV  -14.62mA   -13.73mA   -14.9mA
-551.5mV  -13.37mA   -13.65mA   -13.72mA
-354.6mV  -10.22mA   -10.29mA   -10.71mA
590.9mV   14.46mA    14.13mA    15.79mA
945.5mV   19.18mA    18.53mA    21.45mA
1.339V    20.84mA    20.05mA    23.47mA
1.733V    19.01mA    16.97mA    23.14mA
2.009V    15.7mA     6.74mA     19.1mA
2.364V    4.4mA      2.5mA      13.7mA
[Pullup]
-1.164V   6.1mA      3.409mA    10.51mA
-887.9mV  20.5mA     9.662mA    19.47mA
-730.3mV  21.97mA    17.56mA    20.29mA
-612.1mV  21.14mA    19.84mA    19.93mA
-375.8mV  15.68mA    14.87mA    15.58mA
215.2mV   -7.105mA   -6.743mA   -7.481mA
727.3mV   -16.61mA   -16.01mA   -17.94mA
1.515V    -19.67mA   -18.44mA   -21.92mA
1.791V    -18.11mA   -16.51mA   -20.92mA
1.988V    -17.45mA   -11.08mA   -19.92mA
2.224V    -10.4mA    -7.291mA   -19.29mA
2.382V    -7.6mA     -6.348mA   -12.78mA
[Ramp]
R_load=50.000Ohm
dV/dt_r   390.690mV/124.000ps  371.159mV/154.500ps  429.090mV/105.000ps
dV/dt_f   390.690mV/126.500ps  371.129mV/161.000ps  429.090mV/102.000ps
[Rising waveform]
R_fixture=50.000Ohm
V_fixture=1.200
V_fixture_min=1.140
V_fixture_max=1.300
0s        503.7mV    486mV      509.3mV
52ps      499.5mV    483.2mV    570.1mV
115ps     494.2mV    479.2mV    951mV
154ps     506.1mV    477.6mV    1.106V
230ps     724.3mV    486.6mV    1.21V
281ps     958.2mV    523.8mV    1.228V
332ps     1.077V     627.7mV    1.236V
434ps     1.141V     957.3mV    1.24V
523ps     1.152V     1.067V     1.24V
1.249ns   1.156V     1.106V     1.24V
[Rising waveform]
R_fixture=50.000Ohm
V_fixture=0
0s        830.8uV    788.4uV    -5.389mV
64ps      -135.5uV   800.2uV    41.18mV
192ps     10.91mV    -6.117mV   503.2mV
319ps     357.2mV    16.56mV    665.8mV
383ps     496.9mV    117.7mV    688.5mV
447ps     574.8mV    270.2mV    698.4mV
536ps     622.6mV    447.2mV    703.6mV
626ps     640.1mV    545mV      705.6mV
817ps     649.3mV    606.9mV    707.2mV
1.249ns   651.5mV    618.9mV    707.6mV
[Falling waveform]
R_fixture=50.000Ohm
V_fixture=1.200
V_fixture_min=1.140
V_fixture_max=1.300
0s        1.156V     1.106V     1.245V
64ps      1.156V     1.106V     1.202V
179ps     1.157V     1.112V     760.1mV
230ps     1.078V     1.118V     638mV
294ps     890.9mV    1.102V     566.7mV
370ps     695.1mV    999.2mV    536mV
434ps     597.7mV    858.3mV    526.8mV
536ps     536.3mV    664.4mV    521.1mV
638ps     516.7mV    560.7mV    518.9mV
1.249ns   505.6mV    490.2mV    517.8mV
[Falling waveform]
R_fixture=50.000Ohm
V_fixture=0
0s        651mV      618.9mV    718.2mV
52ps      655.9mV    621.4mV    617.4mV
103ps     666.4mV    627.9mV    305.6mV
141ps     658.5mV    633.9mV    145.5mV
217ps     433.1mV    626.7mV    32.74mV
268ps     206.8mV    564.4mV    13.31mV
319ps     85.4mV     426mV      5.641mV
409ps     19.55mV    143.1mV    1.254mV
498ps     5.542mV    37.64mV    304.8uV
1.249ns   2.189uV    22.28uV    630.8nV
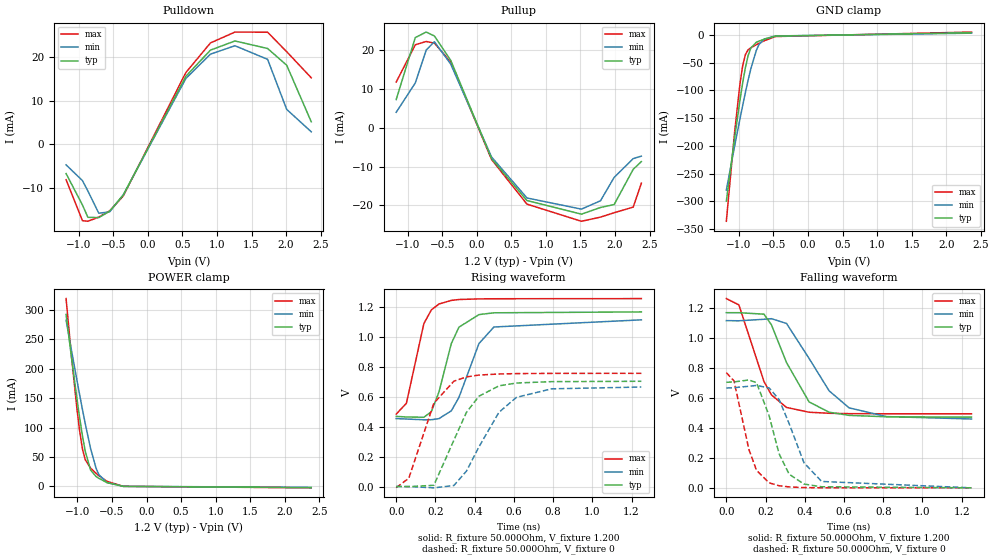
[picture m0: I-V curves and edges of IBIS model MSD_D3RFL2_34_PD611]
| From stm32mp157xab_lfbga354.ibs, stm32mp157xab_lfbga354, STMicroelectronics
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[Model] MSD_D3RFL2_34_PD611
Model_type   I/O
C_comp 2.448pF   2.362pF   2.573pF
Vinh = 820.000mV
Vinl = 380.000mV
Vmeas = 600.000mV
Vref = 600.000mV
[Model Spec]
Vinh   820.000mV   790.000mV   870.000mV
Vinl   380.000mV   350.000mV   430.000mV
Vmeas   600.000mV   570.000mV   650.000mV
Vref   600.000mV   570.000mV   650.000mV
[Temperature Range]   25.000   125.000   -40.000
[Voltage Range]   1.200V   1.140V   1.300V
[GND Clamp Reference]   0.00V   0.00V   0.00V
[Pulldown Reference]   0.00V   0.00V   0.00V
[POWER Clamp Reference]   1.200V   1.140V   1.300V
[Pullup Reference]   1.200V   1.140V   1.300V
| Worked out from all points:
|   slope of the pulldown table from 0 to 0.18 V, typ, clamps not added: 31.3 ohm
|   slope of the pullup table from 0 to 0.18 V, typ, clamps not added: 26.5 ohm
|   GND clamp passes 1 mA (typ) near -0.40 V on its own axis
|   POWER clamp passes 1 mA (typ) near -0.41 V on its own axis
|   rising waveform, R_fixture 50.000Ohm, V_fixture 1.200: 20-80 % time 90.6ps typ, 117ps min, 77.8ps max; typ from 0.47 V to 1.17 V
|   rising waveform, R_fixture 50.000Ohm, V_fixture 0: 20-80 % time 145ps typ, 176ps min, 125ps max; typ from 0.001 V to 0.705 V
|   falling waveform, R_fixture 50.000Ohm, V_fixture 1.200: 20-80 % time 146ps typ, 192ps min, 121ps max; typ from 1.17 V to 0.472 V
|   falling waveform, R_fixture 50.000Ohm, V_fixture 0: 20-80 % time 95.3ps typ, 121ps min, 81.5ps max; typ from 0.704 V to 0 V
[GND Clamp]
-1.182V   -299.5mA   -279.6mA   -335.7mA
-1.064V   -187.3mA   -201.7mA   -177.4mA
-984.9mV  -117.8mA   -151.5mA   -88.49mA
-945.5mV  -86.46mA   -127.3mA   -55.67mA
-906.1mV  -59.05mA   -103.8mA   -35.55mA
-866.7mV  -37.55mA   -81.66mA   -27.13mA
-827.3mV  -23.74mA   -61.1mA    -23.33mA
-748.5mV  -13.56mA   -28.1mA    -17.89mA
-709.1mV  -11.37mA   -17.48mA   -15.38mA
-630.3mV  -7.842mA   -7.517mA   -10.66mA
-472.7mV  -2.44mA    -2.145mA   -3.165mA
2.364V    3.741mA    2.874mA    4.907mA
[Power Clamp]
-1.164V   292.4mA    282.5mA    319.2mA
-1.085V   218.6mA    230.8mA    220mA
-1.006V   148.4mA    180mA      131.1mA
-966.7mV  115.9mA    155.1mA    93.3mA
-927.3mV  86.08mA    130.8mA    63.93mA
-887.9mV  60.35mA    107.3mA    45.81mA
-809.1mV  27.78mA    64.27mA    31.09mA
-730.3mV  17.01mA    31.11mA    22.38mA
-690.9mV  13.91mA    20.28mA    18.51mA
-572.7mV  6.625mA    6.535mA    8.753mA
-336.4mV  188.6uA    356.2uA    213.6uA
2.382V    -1.927mA   -1.589mA   -2.285mA
[Pulldown]
-1.182V   -6.7mA     -4.7mA     -8.1mA
-945.5mV  -13.9mA    -8.3mA     -17.52mA
-866.7mV  -16.74mA   -10.69mA   -17.65mA
-709.1mV  -16.81mA   -15.8mA    -16.69mA
-551.5mV  -15.33mA   -15.49mA   -15.28mA
-354.6mV  -11.63mA   -11.56mA   -11.83mA
551.5mV   15.66mA    15.15mA    16.52mA
906.1mV   21.65mA    20.73mA    23.3mA
1.261V    23.75mA    22.65mA    25.8mA
1.733V    22.02mA    19.53mA    25.76mA
2.009V    18.18mA    8.04mA     21.28mA
2.364V    5.2mA      2.9mA      15.3mA
[Pullup]
-1.164V   7.3mA      4.009mA    11.8mA
-887.9mV  23.27mA    11.57mA    21.42mA
-730.3mV  24.7mA     20.06mA    22.27mA
-612.1mV  23.69mA    22.21mA    21.84mA
-375.8mV  17.41mA    16.45mA    16.97mA
215.2mV   -7.946mA   -7.529mA   -8.168mA
727.3mV   -18.75mA   -18.09mA   -19.68mA
1.515V    -22.27mA   -20.97mA   -24.1mA
1.791V    -20.54mA   -18.81mA   -23.03mA
1.988V    -19.79mA   -12.79mA   -21.9mA
2.264V    -10.7mA    -7.943mA   -20.45mA
2.382V    -8.7mA     -7.295mA   -14.29mA
[Ramp]
R_load=50.000Ohm
dV/dt_r   420.750mV/118.500ps  397.499mV/147.500ps  456.450mV/101.500ps
dV/dt_f   420.750mV/121.000ps  397.469mV/158.000ps  456.450mV/101.500ps
[Rising waveform]
R_fixture=50.000Ohm
V_fixture=1.200
V_fixture_min=1.140
V_fixture_max=1.300
0s        470.1mV    455.2mV    485.2mV
52ps      466mV      452.4mV    557.8mV
141ps     464.1mV    447.3mV    1.091V
179ps     501.2mV    447.7mV    1.182V
218ps     633.1mV    455.1mV    1.222V
281ps     957.6mV    507.2mV    1.246V
320ps     1.067V     597.6mV    1.252V
422ps     1.151V     957.4mV    1.256V
498ps     1.163V     1.068V     1.257V
1.25ns    1.169V     1.116V     1.258V
[Rising waveform]
R_fixture=50.000Ohm
V_fixture=0
0s        886.3uV    894.5uV    -6.476mV
64ps      11.62uV    750.7uV    55.97mV
192ps     9.077mV    -7.984mV   558.5mV
294ps     310.5mV    7.443mV    705.3mV
358ps     496.9mV    103.3mV    734mV
422ps     605.1mV    266.5mV    746.5mV
524ps     674.4mV    497.6mV    753.7mV
613ps     693.3mV    597.3mV    756.2mV
792ps     702.5mV    654.4mV    757.7mV
1.25ns    704.9mV    666.5mV    757.8mV
[Falling waveform]
R_fixture=50.000Ohm
V_fixture=1.200
V_fixture_min=1.140
V_fixture_max=1.300
0s        1.169V     1.116V     1.263V
64ps      1.169V     1.115V     1.221V
192ps     1.159V     1.125V     709.6mV
230ps     1.088V     1.129V     620.1mV
307ps     835.6mV    1.097V     536.6mV
422ps     573.4mV    863.6mV    504.6mV
524ps     504.8mV    647.6mV    497.7mV
626ps     483.6mV    533.7mV    495.2mV
817ps     474.3mV    475.5mV    494.2mV
1.25ns    471.8mV    459.6mV    494mV
[Falling waveform]
R_fixture=50.000Ohm
V_fixture=0
0s        704.3mV    666.4mV    768.7mV
39ps      706.7mV    668.3mV    714.1mV
115ps     720.3mV    678.1mV    256.4mV
154ps     701.7mV    683.2mV    116.6mV
218ps     482mV      667.1mV    33.53mV
269ps     227.3mV    589.5mV    13.96mV
320ps     91.23mV    429.2mV    6.092mV
396ps     25.12mV    166.8mV    1.793mV
486ps     7.114mV    42.5mV     422.2uV
1.25ns    2.918uV    25.99uV    848.5nV
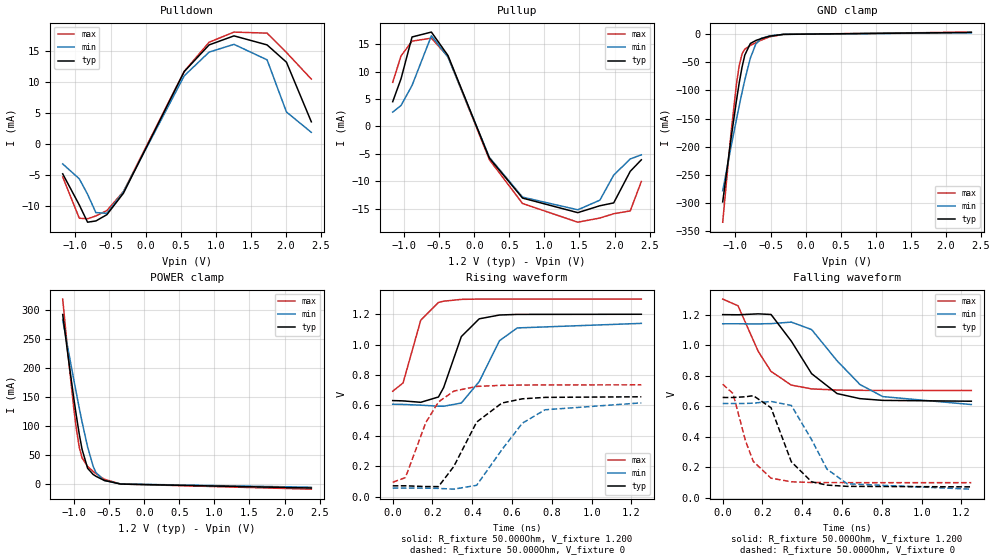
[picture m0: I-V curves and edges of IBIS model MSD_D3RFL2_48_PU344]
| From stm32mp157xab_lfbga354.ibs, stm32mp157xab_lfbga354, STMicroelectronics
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[Model] MSD_D3RFL2_48_PU344
Model_type   I/O
C_comp 2.348pF   2.261pF   2.473pF
Vinh = 820.000mV
Vinl = 380.000mV
Vmeas = 600.000mV
Vref = 600.000mV
[Model Spec]
Vinh   820.000mV   790.000mV   870.000mV
Vinl   380.000mV   350.000mV   430.000mV
Vmeas   600.000mV   570.000mV   650.000mV
Vref   600.000mV   570.000mV   650.000mV
[Temperature Range]   25.000   125.000   -40.000
[Voltage Range]   1.200V   1.140V   1.300V
[GND Clamp Reference]   0.00V   0.00V   0.00V
[Pulldown Reference]   0.00V   0.00V   0.00V
[POWER Clamp Reference]   1.200V   1.140V   1.300V
[Pullup Reference]   1.200V   1.140V   1.300V
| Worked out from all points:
|   slope of the pulldown table from 0 to 0.18 V, typ, clamps not added: 41.6 ohm
|   slope of the pullup table from 0 to 0.18 V, typ, clamps not added: 36.2 ohm
|   GND clamp passes 1 mA (typ) near -0.41 V on its own axis
|   POWER clamp passes 1 mA (typ) near -0.41 V on its own axis
|   rising waveform, R_fixture 50.000Ohm, V_fixture 1.200: 20-80 % time 95.1ps typ, 125ps min, 80ps max; typ from 0.632 V to 1.2 V
|   rising waveform, R_fixture 50.000Ohm, V_fixture 0: 20-80 % time 152ps typ, 187ps min, 125ps max; typ from 0.071 V to 0.657 V
|   falling waveform, R_fixture 50.000Ohm, V_fixture 1.200: 20-80 % time 175ps typ, 223ps min, 141ps max; typ from 1.2 V to 0.632 V
|   falling waveform, R_fixture 50.000Ohm, V_fixture 0: 20-80 % time 108ps typ, 134ps min, 90.3ps max; typ from 0.657 V to 0.071 V
[GND Clamp]
-1.182V   -298.5mA   -278.7mA   -334.6mA
-1.064V   -186.4mA   -201mA     -176.4mA
-984.9mV  -117.1mA   -150.9mA   -87.65mA
-945.5mV  -85.8mA    -126.7mA   -54.89mA
-906.1mV  -58.45mA   -103.4mA   -34.82mA
-866.7mV  -36.99mA   -81.15mA   -26.46mA
-787.9mV  -16.43mA   -42.51mA   -19.96mA
-709.1mV  -11.02mA   -17.14mA   -14.94mA
-630.3mV  -7.563mA   -7.255mA   -10.33mA
-512.1mV  -3.391mA   -2.874mA   -4.513mA
-315.1mV  -135.6uA   -195uA     -130uA
2.364V    3.306mA    2.793mA    3.888mA
[Power Clamp]
-1.164V   291.7mA    282.1mA    318.2mA
-1.085V   217.9mA    230.5mA    219.1mA
-1.006V   147.8mA    179.6mA    130.3mA
-966.7mV  115.4mA    154.8mA    92.58mA
-927.3mV  85.61mA    130.5mA    63.27mA
-887.9mV  59.92mA    107mA      45.21mA
-809.1mV  27.42mA    64.02mA    30.59mA
-730.3mV  16.72mA    30.92mA    21.98mA
-690.9mV  13.66mA    20.11mA    18.17mA
-572.7mV  6.48mA     6.432mA    8.549mA
-336.4mV  188.5uA    360.2uA    208.2uA
2.382V    -6.618mA   -5.26mA    -8.576mA
[Pulldown]
-1.182V   -4.8mA     -3.2mA     -5.3mA
-945.5mV  -9.83mA    -5.6mA     -11.97mA
-827.3mV  -12.61mA   -8.1mA     -12.05mA
-709.1mV  -12.41mA   -11.06mA   -11.6mA
-551.5mV  -11.39mA   -11.18mA   -10.73mA
-315.1mV  -7.916mA   -7.698mA   -7.648mA
551.5mV   11.72mA    11.03mA    11.75mA
906.1mV   16.02mA    14.86mA    16.45mA
1.261V    17.48mA    16.11mA    18.09mA
1.733V    16.02mA    13.61mA    17.92mA
2.009V    13.23mA    5.19mA     14.8mA
2.364V    3.6mA      1.9mA      10.5mA
[Pullup]
-1.164V   4.5mA      2.605mA    8.031mA
-1.045V   8.7mA      3.814mA    12.86mA
-887.9mV  16.31mA    7.475mA    15.55mA
-612.1mV  17.2mA     16.54mA    16.09mA
-375.8mV  12.93mA    12.63mA    12.74mA
215.2mV   -5.8mA     -5.653mA   -6.08mA
687.9mV   -13.08mA   -12.91mA   -14.07mA
1.476V    -15.74mA   -15.22mA   -17.48mA
1.791V    -14.48mA   -13.46mA   -16.72mA
1.988V    -13.96mA   -8.899mA   -15.94mA
2.224V    -8.2mA     -5.943mA   -15.42mA
2.382V    -6.1mA     -5.195mA   -10.06mA
[Ramp]
R_load=50.000Ohm
dV/dt_r   346.386mV/124.000ps  328.383mV/157.000ps  370.293mV/102.500ps
dV/dt_f   346.386mV/142.500ps  328.350mV/180.500ps  370.293mV/115.500ps
[Rising waveform]
R_fixture=50.000Ohm
V_fixture=1.200
V_fixture_min=1.140
V_fixture_max=1.300
0s        632mV      607.9mV    693.5mV
52ps      629.9mV    606.6mV    747.7mV
141ps     620.6mV    601.6mV    1.161V
230ps     655.6mV    595.2mV    1.278V
256ps     717.2mV    594.5mV    1.286V
345ps     1.053V     615.8mV    1.298V
435ps     1.17V      757.2mV    1.3V
537ps     1.195V     1.026V     1.3V
626ps     1.199V     1.11V      1.3V
1.25ns    1.2V       1.14V      1.3V
[Rising waveform]
R_fixture=50.000Ohm
V_fixture=0
0s        70.83mV    55.59mV    94.45mV
64ps      71.16mV    55.84mV    125mV
166ps     66.06mV    55.7mV     485.8mV
230ps     65.85mV    54.15mV    623mV
307ps     198mV      48.94mV    693.9mV
422ps     490.4mV    74.39mV    725.1mV
549ps     615.8mV    308.8mV    732.3mV
652ps     643.6mV    483.3mV    734.2mV
766ps     653mV      571.5mV    735.1mV
1.25ns    656.9mV    616.9mV    735.5mV
[Falling waveform]
R_fixture=50.000Ohm
V_fixture=1.200
V_fixture_min=1.140
V_fixture_max=1.300
0s        1.2V       1.14V      1.302V
77ps      1.199V     1.14V      1.258V
179ps     1.205V     1.139V     957.9mV
243ps     1.201V     1.141V     827.4mV
345ps     1.026V     1.151V     738mV
447ps     812.9mV    1.102V     713mV
575ps     682.4mV    897.4mV    705.4mV
690ps     649.1mV    741.9mV    703.5mV
805ps     637.7mV    662.5mV    703mV
1.25ns    632.2mV    610.4mV    702.9mV
[Falling waveform]
R_fixture=50.000Ohm
V_fixture=0
0s        656.8mV    617.7mV    743.6mV
52ps      656.6mV    617.3mV    682.5mV
115ps     661.6mV    617.6mV    370.4mV
154ps     668.5mV    619.6mV    237.3mV
243ps     589.4mV    630.7mV    127.7mV
345ps     235.1mV    604.6mV    104mV
447ps     104mV      380.3mV    99.39mV
524ps     82.41mV    187.5mV    98.62mV
626ps     74.01mV    90.57mV    98.39mV
1.25ns    70.69mV    55.62mV    98.29mV
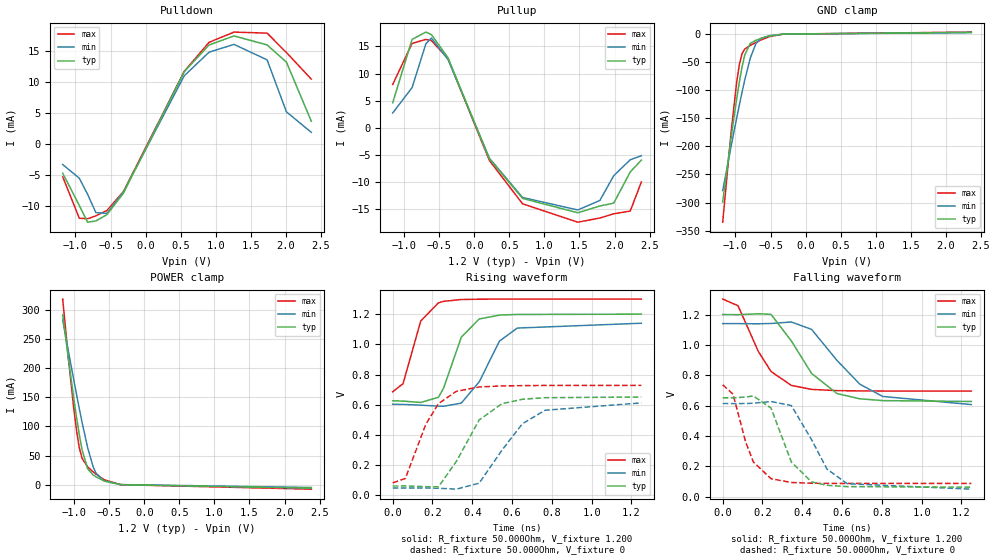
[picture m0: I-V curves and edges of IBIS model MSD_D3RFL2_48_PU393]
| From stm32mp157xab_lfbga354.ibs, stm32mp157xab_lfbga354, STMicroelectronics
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[Model] MSD_D3RFL2_48_PU393
Model_type   I/O
C_comp 2.377pF   2.291pF   2.503pF
Vinh = 820.000mV
Vinl = 380.000mV
Vmeas = 600.000mV
Vref = 600.000mV
[Model Spec]
Vinh   820.000mV   790.000mV   870.000mV
Vinl   380.000mV   350.000mV   430.000mV
Vmeas   600.000mV   570.000mV   650.000mV
Vref   600.000mV   570.000mV   650.000mV
[Temperature Range]   25.000   125.000   -40.000
[Voltage Range]   1.200V   1.140V   1.300V
[GND Clamp Reference]   0.00V   0.00V   0.00V
[Pulldown Reference]   0.00V   0.00V   0.00V
[POWER Clamp Reference]   1.200V   1.140V   1.300V
[Pullup Reference]   1.200V   1.140V   1.300V
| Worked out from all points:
|   slope of the pulldown table from 0 to 0.18 V, typ, clamps not added: 41.6 ohm
|   slope of the pullup table from 0 to 0.18 V, typ, clamps not added: 36.3 ohm
|   GND clamp passes 1 mA (typ) near -0.41 V on its own axis
|   POWER clamp passes 1 mA (typ) near -0.41 V on its own axis
|   rising waveform, R_fixture 50.000Ohm, V_fixture 1.200: 20-80 % time 96.5ps typ, 126ps min, 81.1ps max; typ from 0.627 V to 1.2 V
|   rising waveform, R_fixture 50.000Ohm, V_fixture 0: 20-80 % time 155ps typ, 190ps min, 129ps max; typ from 0.062 V to 0.651 V
|   falling waveform, R_fixture 50.000Ohm, V_fixture 1.200: 20-80 % time 176ps typ, 224ps min, 143ps max; typ from 1.2 V to 0.627 V
|   falling waveform, R_fixture 50.000Ohm, V_fixture 0: 20-80 % time 108ps typ, 135ps min, 91.2ps max; typ from 0.651 V to 0.062 V
[GND Clamp]
-1.182V   -298.8mA   -278.8mA   -334.9mA
-1.064V   -186.6mA   -201.1mA   -176.7mA
-984.9mV  -117.3mA   -151.1mA   -87.88mA
-945.5mV  -85.98mA   -126.9mA   -55.1mA
-906.1mV  -58.6mA    -103.4mA   -35.03mA
-866.7mV  -37.14mA   -81.28mA   -26.65mA
-787.9mV  -16.55mA   -42.62mA   -20.11mA
-709.1mV  -11.11mA   -17.23mA   -15.06mA
-630.3mV  -7.64mA    -7.317mA   -10.42mA
-512.1mV  -3.431mA   -2.91mA    -4.569mA
-315.1mV  -140uA     -201.2uA   -134.4uA
2.364V    2.893mA    2.444mA    3.402mA
[Power Clamp]
-1.164V   291.9mA    282.3mA    318.5mA
-1.085V   218.2mA    230.6mA    219.4mA
-1.006V   148mA      179.8mA    130.6mA
-966.7mV  115.5mA    154.9mA    92.81mA
-927.3mV  85.77mA    130.6mA    63.48mA
-887.9mV  60.06mA    107.1mA    45.4mA
-809.1mV  27.54mA    64.12mA    30.75mA
-730.3mV  16.82mA    31mA       22.11mA
-690.9mV  13.74mA    20.18mA    18.27mA
-572.7mV  6.53mA     6.478mA    8.613mA
-336.4mV  191.9uA    365.4uA    212.3uA
2.382V    -5.79mA    -4.601mA   -7.505mA
[Pulldown]
-1.182V   -4.7mA     -3.3mA     -5.3mA
-945.5mV  -9.9mA     -5.5mA     -11.97mA
-827.3mV  -12.61mA   -8.1mA     -12.05mA
-709.1mV  -12.41mA   -11.06mA   -11.59mA
-551.5mV  -11.39mA   -11.19mA   -10.72mA
-315.1mV  -7.91mA    -7.697mA   -7.642mA
551.5mV   11.71mA    11.04mA    11.75mA
906.1mV   16.02mA    14.86mA    16.45mA
1.261V    17.48mA    16.11mA    18.1mA
1.733V    16.03mA    13.62mA    17.93mA
2.009V    13.24mA    5.22mA     14.8mA
2.364V    3.7mA      1.9mA      10.5mA
[Pullup]
-1.164V   4.6mA      2.705mA    7.977mA
-887.9mV  16.31mA    7.39mA     15.56mA
-690.9mV  17.66mA    15.5mA     16.31mA
-612.1mV  17.19mA    16.55mA    16.09mA
-375.8mV  12.93mA    12.62mA    12.74mA
215.2mV   -5.799mA   -5.653mA   -6.08mA
687.9mV   -13.08mA   -12.91mA   -14.07mA
1.476V    -15.74mA   -15.22mA   -17.48mA
1.791V    -14.48mA   -13.46mA   -16.71mA
1.988V    -13.96mA   -8.894mA   -15.93mA
2.224V    -8.2mA     -5.943mA   -15.42mA
2.382V    -6mA       -5.195mA   -10.06mA
[Ramp]
R_load=50.000Ohm
dV/dt_r   348.861mV/126.000ps  330.390mV/159.000ps  373.860mV/105.000ps
dV/dt_f   348.831mV/143.500ps  330.327mV/181.500ps  373.860mV/117.000ps
[Rising waveform]
R_fixture=50.000Ohm
V_fixture=1.200
V_fixture_min=1.140
V_fixture_max=1.300
0s        626.6mV    603.7mV    686.3mV
52ps      624.5mV    602.4mV    739.7mV
141ps     615.3mV    597.5mV    1.155V
230ps     649.8mV    591.1mV    1.275V
256ps     710.8mV    590.3mV    1.285V
345ps     1.048V     611.3mV    1.297V
435ps     1.168V     752mV      1.299V
537ps     1.194V     1.022V     1.3V
626ps     1.198V     1.108V     1.3V
1.25ns    1.2V       1.14V      1.3V
[Rising waveform]
R_fixture=50.000Ohm
V_fixture=0
0s        62.38mV    48.9mV     82.93mV
64ps      62.75mV    49.16mV    112.7mV
166ps     57.69mV    49.07mV    469.6mV
230ps     57.11mV    47.54mV    607.6mV
320ps     225mV      41.35mV    689.3mV
435ps     500.1mV    81.19mV    718.1mV
549ps     606.9mV    299mV      724.9mV
652ps     636.5mV    474.4mV    726.9mV
766ps     647mV      563.9mV    728mV
1.25ns    651.4mV    612.6mV    728.5mV
[Falling waveform]
R_fixture=50.000Ohm
V_fixture=1.200
V_fixture_min=1.140
V_fixture_max=1.300
0s        1.2V       1.14V      1.302V
77ps      1.199V     1.14V      1.258V
179ps     1.205V     1.139V     956.8mV
243ps     1.201V     1.141V     824.7mV
345ps     1.026V     1.151V     732.8mV
447ps     811.5mV    1.102V     706.6mV
575ps     678.9mV    896.9mV    698.4mV
690ps     644.5mV    740.2mV    696.6mV
805ps     632.7mV    659.8mV    695.9mV
1.25ns    626.9mV    606.7mV    695.6mV
[Falling waveform]
R_fixture=50.000Ohm
V_fixture=0
0s        651.3mV    613.5mV    736.6mV
52ps      651.1mV    613.1mV    674.9mV
115ps     656.1mV    613.4mV    361.8mV
154ps     663.2mV    615.4mV    228.5mV
243ps     583.3mV    626.6mV    117.8mV
345ps     228.1mV    600.2mV    93mV
447ps     96.6mV     374.7mV    87.96mV
524ps     74.53mV    181.8mV    87.1mV
626ps     65.75mV    84.82mV    86.83mV
1.25ns    62.24mV    48.93mV    86.7mV
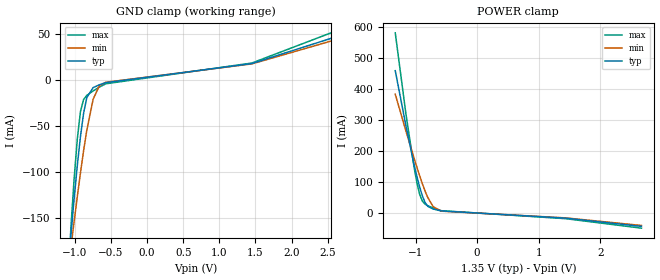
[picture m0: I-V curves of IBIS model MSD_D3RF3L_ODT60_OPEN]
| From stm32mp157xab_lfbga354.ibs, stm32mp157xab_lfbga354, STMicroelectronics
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[Model] MSD_D3RF3L_ODT60_OPEN
Model_type   Input
C_comp 2.526pF   2.473pF   2.598pF
Vinh = 810.000mV
Vinl = 540.000mV
[Model Spec]
Vinh   810.000mV   777.000mV   860.000mV
Vinl   540.000mV   507.000mV   590.000mV
[Temperature Range]   25.000   125.000   -40.000
[Voltage Range]   1.350V   1.283V   1.450V
[GND Clamp Reference]   0.00V   0.00V   0.00V
[POWER Clamp Reference]   1.350V   1.283V   1.450V
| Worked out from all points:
|   GND clamp passes 1 mA (typ) near -0.44 V on its own axis
|   POWER clamp passes 1 mA (typ) near -0.18 V on its own axis
[GND Clamp]
-1.318V   -431.2mA   -358mA     -546.9mA
-1.055V   -168.7mA   -181.9mA   -160mA
-1.011V   -129.3mA   -154mA     -108mA
-966.7mV  -93.17mA   -126.9mA   -64.41mA
-922.7mV  -61.45mA   -100.9mA   -34.34mA
-878.8mV  -35.99mA   -76.61mA   -21.27mA
-834.9mV  -19.28mA   -54.61mA   -16.92mA
-747mV    -8.474mA   -20.98mA   -12.04mA
-659.1mV  -5.353mA   -6.163mA   -7.86mA
-571.2mV  -3.073mA   -2.665mA   -4.346mA
1.45V     17.57mA    17.21mA    18.18mA
2.68V     48.26mA    45mA       54.86mA
[Power Clamp]
-1.33V    460.5mA    384.3mA    582.5mA
-1.155V   280.6mA    264.1mA    318mA
-1.023V   155.7mA    176.6mA    146.6mA
-978.8mV  118.8mA    148.5mA    98.96mA
-934.9mV  85.4mA     121.4mA    61.46mA
-890.9mV  56.62mA    95.75mA    39.36mA
-847mV    34.81mA    72.05mA    29.43mA
-803mV    22.21mA    51.11mA    24.22mA
-715.1mV  13.33mA    21.02mA    16.56mA
-583.3mV  7.213mA    6.431mA    7.996mA
1.438V    -16.14mA   -15.26mA   -17.88mA
2.668V    -42.73mA   -39.78mA   -48.47mA
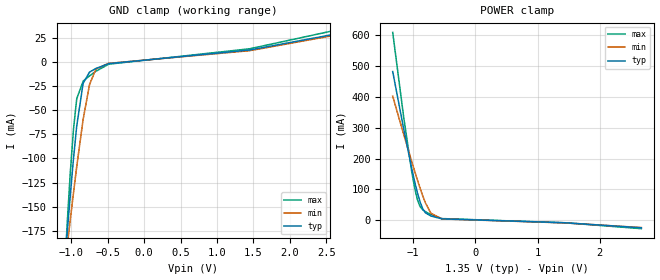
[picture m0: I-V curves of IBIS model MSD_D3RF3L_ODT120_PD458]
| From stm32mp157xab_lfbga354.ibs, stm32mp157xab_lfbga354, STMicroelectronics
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[Model] MSD_D3RF3L_ODT120_PD458
Model_type   Input
C_comp 2.350pF   2.272pF   2.440pF
Vinh = 810.000mV
Vinl = 540.000mV
[Temperature Range]   25.000   125.000   -40.000
[Voltage Range]   1.350V   1.283V   1.450V
[GND Clamp Reference]   0.00V   0.00V   0.00V
[POWER Clamp Reference]   1.350V   1.283V   1.450V
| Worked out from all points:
|   GND clamp passes 1 mA (typ) near -0.43 V on its own axis
|   POWER clamp passes 1 mA (typ) near -0.32 V on its own axis
[GND Clamp]
-1.318V   -446.4mA   -371.4mA   -564.9mA
-1.098V   -221.3mA   -221.2mA   -229.7mA
-1.055V   -178.6mA   -191.9mA   -169mA
-1.011V   -137.8mA   -163.3mA   -114.4mA
-966.7mV  -99.79mA   -135.3mA   -69.1mA
-922.7mV  -66.28mA   -108.3mA   -38.22mA
-834.9mV  -22.17mA   -59.48mA   -20.04mA
-747mV    -10.58mA   -23.42mA   -14.51mA
-659.1mV  -6.847mA   -7.337mA   -9.707mA
-483.3mV  -1.839mA   -1.559mA   -2.399mA
1.45V     12.26mA    11.56mA    13.54mA
2.68V     29.53mA    28.4mA     33.61mA
[Power Clamp]
-1.33V    481.4mA    401.8mA    608.1mA
-1.155V   297.6mA    279.3mA    336.2mA
-1.023V   166.5mA    189.5mA    156.2mA
-978.8mV  126.8mA    160.4mA    107mA
-934.9mV  90.92mA    132mA      68.16mA
-890.9mV  60.38mA    104.8mA    44.96mA
-847mV    37.48mA    79.2mA     34.07mA
-803mV    24.12mA    56.22mA    27.98mA
-715.1mV  14.07mA    22.82mA    18.79mA
-539.4mV  4.851mA    4.565mA    5.806mA
1.438V    -7.703mA   -8.249mA   -7.847mA
2.668V    -24.09mA   -23.31mA   -26.85mA
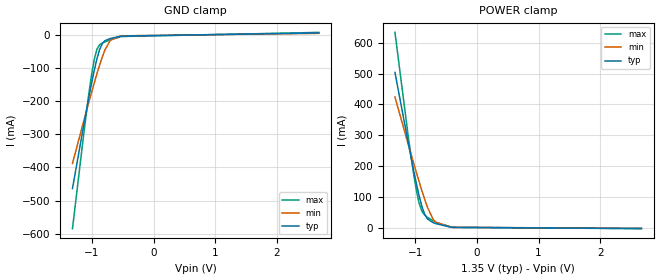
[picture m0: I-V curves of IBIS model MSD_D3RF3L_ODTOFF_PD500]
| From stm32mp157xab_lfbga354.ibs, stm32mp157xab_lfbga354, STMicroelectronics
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[Model] MSD_D3RF3L_ODTOFF_PD500
Model_type   Input
C_comp 2.411pF   2.325pF   2.533pF
Vinh = 810.000mV
Vinl = 540.000mV
[Temperature Range]   25.000   125.000   -40.000
[Voltage Range]   1.350V   1.283V   1.450V
[GND Clamp Reference]   0.00V   0.00V   0.00V
[POWER Clamp Reference]   1.350V   1.283V   1.450V
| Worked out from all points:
|   GND clamp passes 1 mA (typ) near -0.40 V on its own axis
|   POWER clamp passes 1 mA (typ) near -0.41 V on its own axis
[GND Clamp]
-1.318V   -463.8mA   -388.4mA   -584.9mA
-1.142V   -279.5mA   -265.3mA   -309.8mA
-1.055V   -190.9mA   -205mA     -181.5mA
-1.011V   -148.7mA   -175.5mA   -124.4mA
-966.7mV  -109.2mA   -146.6mA   -76.85mA
-922.7mV  -73.85mA   -118.7mA   -44.65mA
-878.8mV  -45.34mA   -92.13mA   -30.44mA
-834.9mV  -26.71mA   -67.51mA   -25.2mA
-790.9mV  -17.83mA   -45.83mA   -21.78mA
-703mV    -11.42mA   -16.65mA   -15.7mA
-527.3mV  -4.091mA   -3.444mA   -5.516mA
2.68V     5.36mA     4.161mA    6.959mA
[Power Clamp]
-1.33V    504mA      423.9mA    634mA
-1.111V   270.9mA    267.9mA    290.3mA
-1.023V   181.4mA    206.6mA    168.5mA
-978.8mV  139.3mA    176.5mA    117.2mA
-934.9mV  100.7mA    147mA      76.86mA
-890.9mV  67.65mA    118.4mA    52.44mA
-847mV    42.9mA     91.24mA    40.51mA
-803mV    28.32mA    66.37mA    33.49mA
-715.1mV  16.69mA    28.43mA    22.64mA
-671.2mV  13.19mA    17.47mA    17.97mA
-407.6mV  914uA      1.197mA    1.122mA
2.668V    -2.695mA   -2.242mA   -3.21mA
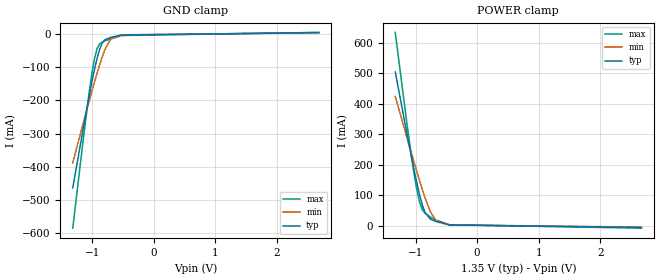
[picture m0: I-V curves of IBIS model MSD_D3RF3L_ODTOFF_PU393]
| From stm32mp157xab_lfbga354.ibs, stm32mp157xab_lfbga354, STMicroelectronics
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[Model] MSD_D3RF3L_ODTOFF_PU393
Model_type   Input
C_comp 2.367pF   2.282pF   2.490pF
Vinh = 810.000mV
Vinl = 540.000mV
[Temperature Range]   25.000   125.000   -40.000
[Voltage Range]   1.350V   1.283V   1.450V
[GND Clamp Reference]   0.00V   0.00V   0.00V
[POWER Clamp Reference]   1.350V   1.283V   1.450V
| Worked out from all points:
|   GND clamp passes 1 mA (typ) near -0.40 V on its own axis
|   POWER clamp passes 1 mA (typ) near -0.41 V on its own axis
[GND Clamp]
-1.318V   -463.3mA   -387.9mA   -584.3mA
-1.142V   -279.1mA   -264.8mA   -309.3mA
-1.055V   -190.6mA   -204.6mA   -181.1mA
-1.011V   -148.5mA   -175.2mA   -124.1mA
-966.7mV  -108.9mA   -146.4mA   -76.49mA
-922.7mV  -73.58mA   -118.5mA   -44.32mA
-878.8mV  -45.09mA   -91.9mA    -30.15mA
-834.9mV  -26.49mA   -67.3mA    -24.93mA
-790.9mV  -17.63mA   -45.64mA   -21.53mA
-703mV    -11.26mA   -16.51mA   -15.5mA
-527.3mV  -4.015mA   -3.37mA    -5.426mA
2.68V     3.391mA    2.877mA    4.021mA
[Power Clamp]
-1.33V    503.7mA    423.7mA    633.5mA
-1.155V   316.7mA    298.6mA    356.3mA
-1.067V   225.3mA    237mA      226.6mA
-1.023V   181.2mA    206.5mA    168.2mA
-978.8mV  139.1mA    176.4mA    116.8mA
-934.9mV  100.5mA    146.9mA    76.56mA
-890.9mV  67.49mA    118.3mA    52.2mA
-847mV    42.75mA    91.18mA    40.3mA
-759.1mV  20.99mA    44.88mA    27.61mA
-671.2mV  13.11mA    17.41mA    17.84mA
-451.5mV  1.863mA    2.107mA    2.351mA
2.668V    -6.686mA   -5.347mA   -8.615mA
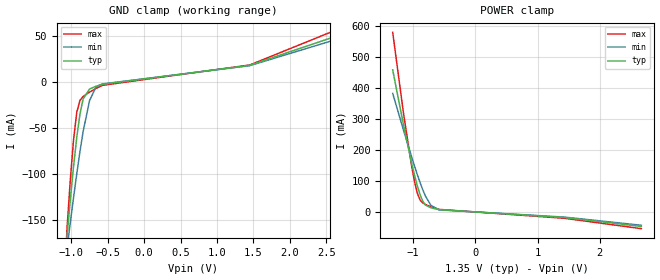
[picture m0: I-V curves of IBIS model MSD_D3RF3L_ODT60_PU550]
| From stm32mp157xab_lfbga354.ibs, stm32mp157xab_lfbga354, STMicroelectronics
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[Model] MSD_D3RF3L_ODT60_PU550
Model_type   Input
C_comp 2.379pF   2.328pF   2.449pF
Vinh = 810.000mV
Vinl = 540.000mV
[Temperature Range]   25.000   125.000   -40.000
[Voltage Range]   1.350V   1.283V   1.450V
[GND Clamp Reference]   0.00V   0.00V   0.00V
[POWER Clamp Reference]   1.350V   1.283V   1.450V
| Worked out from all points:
|   GND clamp passes 1 mA (typ) near -0.45 V on its own axis
|   POWER clamp passes 1 mA (typ) near -0.18 V on its own axis
[GND Clamp]
-1.318V   -429.7mA   -356.6mA   -545mA
-1.055V   -167.6mA   -181mA     -158.7mA
-1.011V   -128.4mA   -153.2mA   -106.8mA
-966.7mV  -92.31mA   -126.1mA   -63.31mA
-922.7mV  -60.66mA   -100.3mA   -33.3mA
-878.8mV  -35.27mA   -75.99mA   -20.32mA
-834.9mV  -18.64mA   -54.04mA   -16.06mA
-747mV    -7.954mA   -20.53mA   -11.36mA
-659.1mV  -4.97mA    -5.815mA   -7.35mA
-571.2mV  -2.806mA   -2.423mA   -3.98mA
1.45V     17.76mA    17.44mA    18.18mA
2.68V     50.75mA    47mA       57.72mA
[Power Clamp]
-1.33V    459.1mA    383.2mA    580.6mA
-1.155V   279.5mA    263.1mA    316.5mA
-1.023V   154.7mA    175.8mA    145.4mA
-978.8mV  117.9mA    147.8mA    97.89mA
-934.9mV  84.55mA    120.7mA    60.45mA
-890.9mV  55.83mA    95.07mA    38.42mA
-847mV    34.09mA    71.48mA    28.58mA
-803mV    21.57mA    50.63mA    23.46mA
-715.1mV  12.83mA    20.65mA    15.97mA
-583.3mV  6.918mA    6.214mA    7.657mA
1.438V    -18.73mA   -17.34mA   -21.21mA
2.668V    -47.51mA   -43.63mA   -54.66mA
